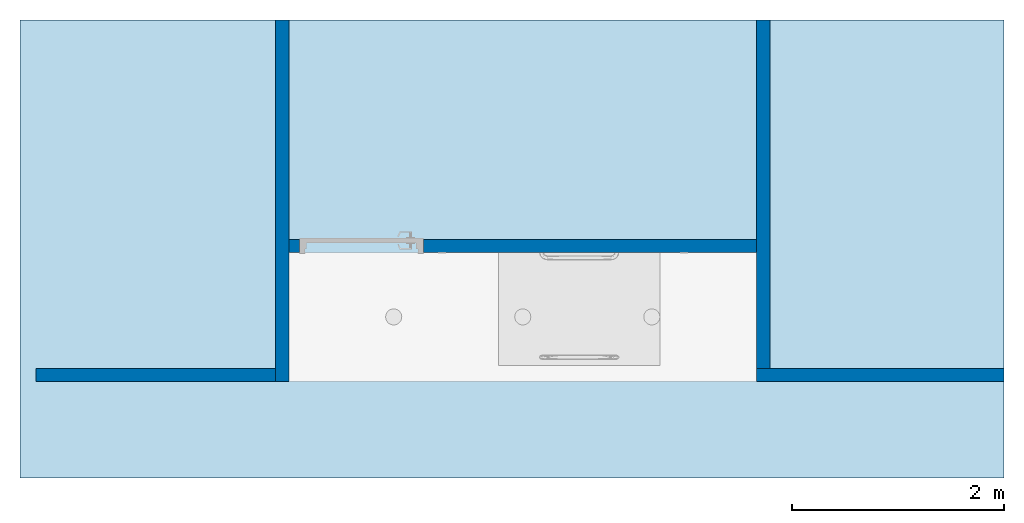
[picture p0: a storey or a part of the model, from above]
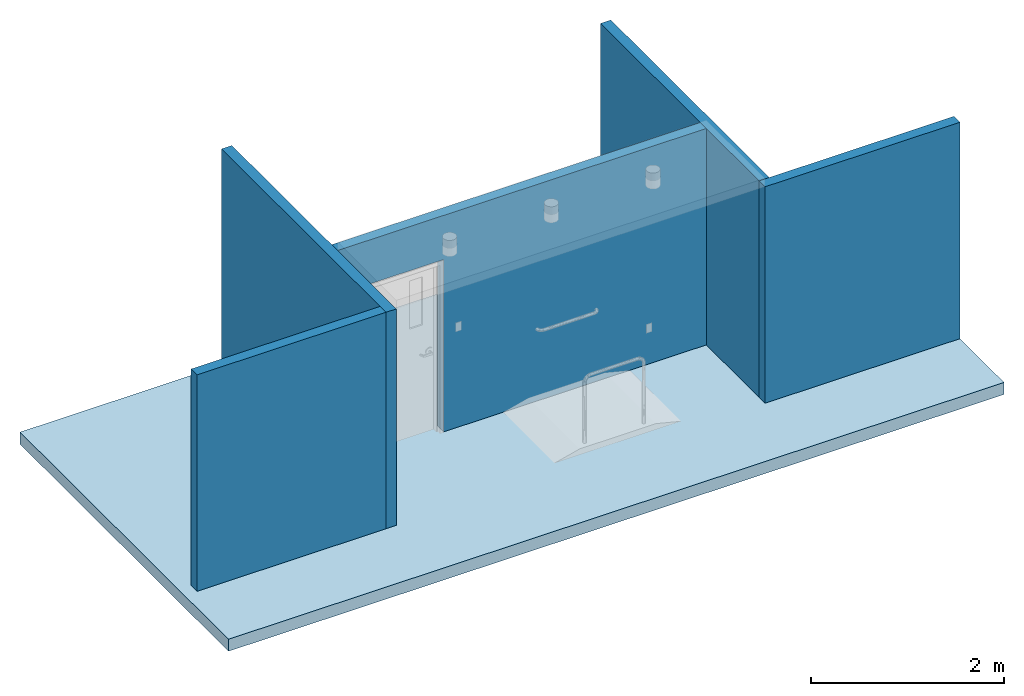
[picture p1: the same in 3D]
Properties of the parts of a building model (IFC2X3)

# File
Description: ViewDefinition [CoordinationView_V2.0]
File name: (ROOM CODE)
Time: 2018-06-28T02:36:13
Written by: The EXPRESS Data Manager Version 5.02.0100.07 : 28 Aug 2013
Made in: 20170223_1515(x64) - Exporter 18.0.0.420 - Alternate UI 18.0.0.420
Comment: STEP Physical File produced by: The EXPRESS Data Manager Version 5.02.0100.07 : 28 Aug 2013 * Module: EDMstepFileFactory/EDMstandAlone * Creation date: Thu Jun 28 02:36:13 2018 * Host: L106-OKC * Database: C:\Users\BHR~1.SPU\AppData\Local\Temp\{4D9C6B0B-E51D-43FB-BA6D-24FEBF8DF5A0}\ifc * Database version: 5507 * Database creation date: Thu Jun 28 02:36:12 2018 * Schema: IFC2X3 * Model: DataRepository.ifc * Model creation date: Thu Jun 28 02:36:12 2018 * Header model: DataRepository.ifc_HeaderModel * Header model creation date: Thu Jun 28 02:36:12 2018 * EDMuser: sdai-user * EDMgroup: sdai-group * License ID and type: 5605 : Permanent license. Expiry date: * EDMstepFileFactory options: 020000

# IfcProject, (ROOM CODE)
LongName: ROOM NAME (ROOM CODE); Phase: DRAFT

# IfcSite, Default
RefLatitude: 42, 21, 31, 181945; RefLongitude: -71, -3, -24, -263305; RefElevation: 0 ft

# IfcBuilding, OUTPATIENT / PACT CLINIC (Ch. 265)
LongName: OUTPATIENT / PACT CLINIC (Ch. 265)
Pset_BuildingCommon - NumberOfStoreys: 1

# IfcBuildingStorey, DATUM
In: OUTPATIENT / PACT CLINIC (Ch. 265)
LongName: DATUM; Elevation: 0 ft

# IfcSpace, PEHW2
In: DATUM
LongName: ALCOVE, SCALE; InteriorOrExteriorSpace: INTERNAL
Pset_SpaceCommon - Reference: ALCOVE, SCALE PEHW2; Category: Rooms

# IfcBuildingElementProxy: Duplex, Outlet, Duplex, Wall:Duplex:1569141
In: PEHW2
Pset_BuildingElementProxyCommon - Reference: Duplex

# IfcBuildingElementProxy: M4020 - Scale, Person Weighing, High Capacity, M4020 - Scale, Person Weighing, High Capacity:M4020 - Scale, Person Weighing, High Capacity:1057961
In: PEHW2
Type - Classification: VV (Uniformat)
Pset_BuildingElementProxyCommon - Reference: M4020 - Scale, Person Weighing, High Capacity

# IfcBuildingElementProxy: Single, Switch, Single:Single:1569244
In: PEHW2
Pset_BuildingElementProxyCommon - Reference: Single

# IfcCovering: Compound Ceiling:GWB on Mtl. Stud, Compound Ceiling:GWB on Mtl. Stud:610427
In: PEHW2
PredefinedType: CEILING; Classification: C3030220 Suspended Ceilings - Gypsum Board (Uniformat); Material: <Unnamed> 0.302083 ft, gyp ceiling 0.0520833 ft
Pset_CoveringCommon - Reference: GWB on Mtl. Stud; Finish: gyp ceiling;; TotalThickness: 0.354167 ft

# IfcDoor: 42" x 84" Narrow Lite, Single - Panel Lite:42" x 84" Narrow Lite:1508653
In: DATUM
Type - ParameterTakesPrecedence: no; Sizeable: no
OverallHeight: 7.16667 ft; OverallWidth: 3.83333 ft
Pset_DoorCommon - IsExternal: no; Reference: 42" x 84" Narrow Lite

# IfcFlowTerminal: 6" (3)
In: PEHW2
Type - Classification: D5020220 Lighting - Incandescent (Uniformat)
Pset_DistributionFlowElementCommon - Reference: 6"
Name (Downlight - Recessed Can:6":...)
1183296
1183299
1183327

# IfcSlab: Floor:Generic - 6", Floor:Generic - 6":1054261
In: DATUM
PredefinedType: FLOOR; Classification: B1010 Floor Construction (Uniformat); Material: <Unnamed> 0.5 ft
Pset_SlabCommon - LoadBearing: no; Reference: Generic - 6"; IsExternal: no; PitchAngle: 0 deg

# IfcWallStandardCase: Basic Wall:Interior - 4 7/8" (5)
In: DATUM
Type - PredefinedType: STANDARD; Material: <Unnamed> 0.40625 ft
Classification: B2010 Exterior Walls (Uniformat)
Pset_WallCommon - Reference: Interior - 4 7/8"; LoadBearing: no; ExtendToStructure: no; IsExternal: yes
Name (Basic Wall:Interior - 4 7/8":...)
610373
610374
610375
610376
610442
